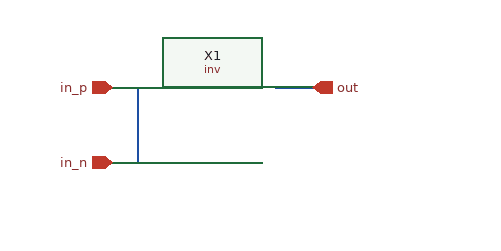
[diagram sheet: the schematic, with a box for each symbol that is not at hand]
v {xschem version=2.9.9 file_version=1.2 }
G {}
K {}
V {}
S {}
E {}
N 340 -80 380 -80 { lab=out}
N 200 -80 240 -80 { lab=in_n}
N 230 -80 230 -20 { lab=in_n}
N 200 -20 230 -20 { lab=in_n}
C {inv/inv.sym} 290 -80 0 0 {name=X1}
C {devices/opin.sym} 370 -80 0 0 {name=p2 lab=out}
C {devices/ipin.sym} 210 -80 0 0 {name=p4 lab=in_p}
C {devices/ipin.sym} 210 -20 0 0 {name=p1 lab=in_n}
